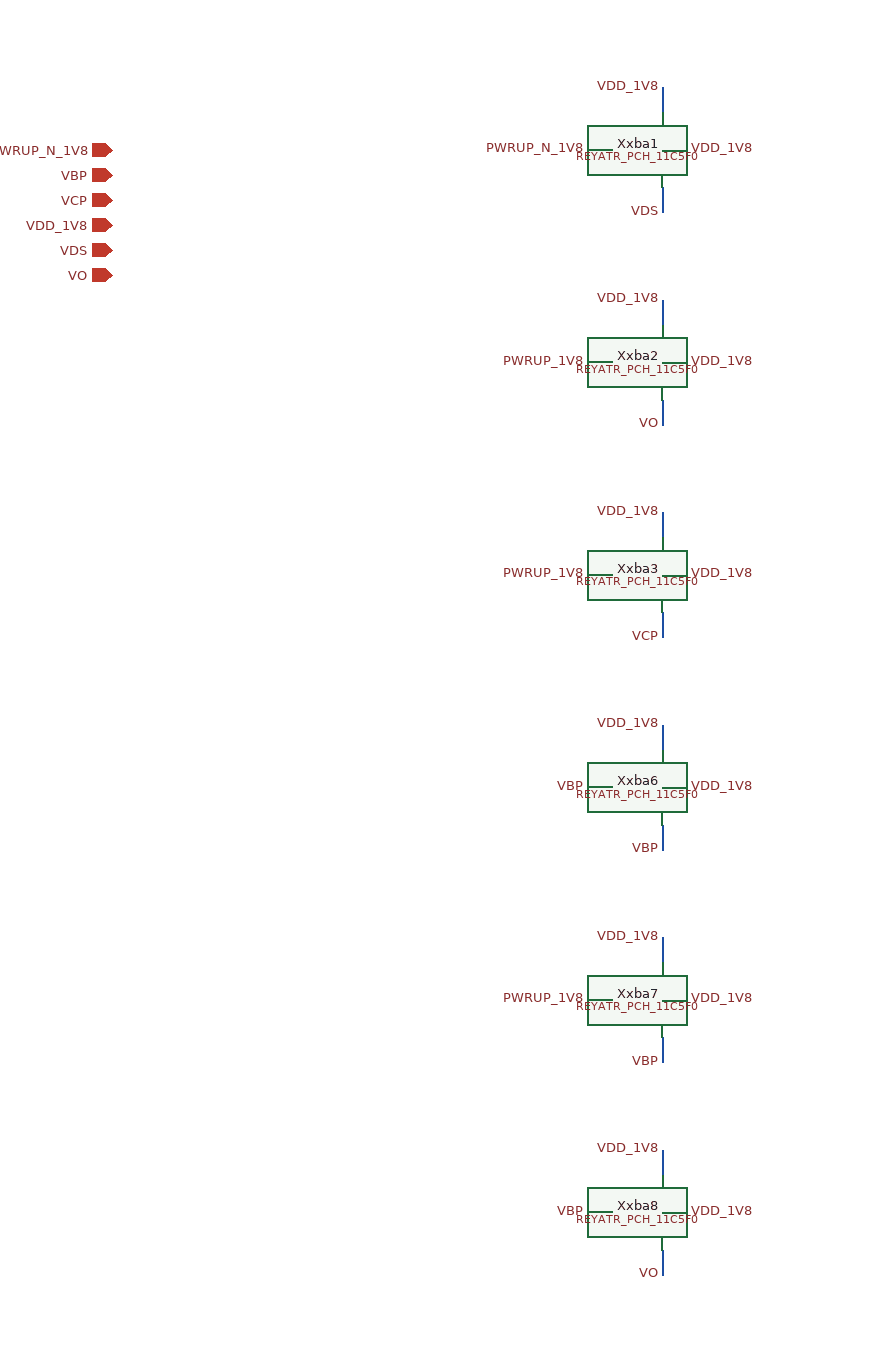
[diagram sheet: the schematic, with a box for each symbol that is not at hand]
v {xschem version=3.0.0 file_version=1.2 }
G {}
K {}
V {}
S {}
E {}
C {devices/iopin.sym} 0 0 0 0 {name=p0 lab=PWRUP_N_1V8}
C {devices/iopin.sym} 0 20 0 0 {name=p1 lab=VBP}
C {devices/iopin.sym} 0 40 0 0 {name=p2 lab=VCP}
C {devices/iopin.sym} 0 60 0 0 {name=p3 lab=VDD_1V8}
C {devices/iopin.sym} 0 80 0 0 {name=p4 lab=VDS}
C {devices/iopin.sym} 0 100 0 0 {name=p5 lab=VO}
C {LELO_TEMP_SKY130A/REYATR_PCH_11C5F0.sym} 400 0 0 0 {name=Xxba1}
N 440.0 50.0 440.0 30.0 {lab=VDS}
C {devices/lab_pin.sym} 440.0 50.0 1 0 {name=l0 sig_type=std_logic lab=VDS }
N 380.0 0.0 400.0 0.0 {lab=PWRUP_N_1V8}
C {devices/lab_pin.sym} 380.0 0.0 0 0 {name=l1 sig_type=std_logic lab=PWRUP_N_1V8 }
N 440.0 -50.0 440.0 -30.0 {lab=VDD_1V8}
C {devices/lab_pin.sym} 440.0 -50.0 3 0 {name=l2 sig_type=std_logic lab=VDD_1V8 }
N 460.0 0.0 440.0 0.0 {lab=VDD_1V8}
C {devices/lab_pin.sym} 460.0 0.0 2 0 {name=l3 sig_type=std_logic lab=VDD_1V8 }
C {LELO_TEMP_SKY130A/REYATR_PCH_11C5F0.sym} 400 170.0 0 0 {name=Xxba2}
N 440.0 220.0 440.0 200.0 {lab=VO}
C {devices/lab_pin.sym} 440.0 220.0 1 0 {name=l4 sig_type=std_logic lab=VO }
N 380.0 170.0 400.0 170.0 {lab=PWRUP_1V8}
C {devices/lab_pin.sym} 380.0 170.0 0 0 {name=l5 sig_type=std_logic lab=PWRUP_1V8 }
N 440.0 120.0 440.0 140.0 {lab=VDD_1V8}
C {devices/lab_pin.sym} 440.0 120.0 3 0 {name=l6 sig_type=std_logic lab=VDD_1V8 }
N 460.0 170.0 440.0 170.0 {lab=VDD_1V8}
C {devices/lab_pin.sym} 460.0 170.0 2 0 {name=l7 sig_type=std_logic lab=VDD_1V8 }
C {LELO_TEMP_SKY130A/REYATR_PCH_11C5F0.sym} 400 340.0 0 0 {name=Xxba3}
N 440.0 390.0 440.0 370.0 {lab=VCP}
C {devices/lab_pin.sym} 440.0 390.0 1 0 {name=l8 sig_type=std_logic lab=VCP }
N 380.0 340.0 400.0 340.0 {lab=PWRUP_1V8}
C {devices/lab_pin.sym} 380.0 340.0 0 0 {name=l9 sig_type=std_logic lab=PWRUP_1V8 }
N 440.0 290.0 440.0 310.0 {lab=VDD_1V8}
C {devices/lab_pin.sym} 440.0 290.0 3 0 {name=l10 sig_type=std_logic lab=VDD_1V8 }
N 460.0 340.0 440.0 340.0 {lab=VDD_1V8}
C {devices/lab_pin.sym} 460.0 340.0 2 0 {name=l11 sig_type=std_logic lab=VDD_1V8 }
C {LELO_TEMP_SKY130A/REYATR_PCH_11C5F0.sym} 400 510.0 0 0 {name=Xxba6}
N 440.0 560.0 440.0 540.0 {lab=VBP}
C {devices/lab_pin.sym} 440.0 560.0 1 0 {name=l12 sig_type=std_logic lab=VBP }
N 380.0 510.0 400.0 510.0 {lab=VBP}
C {devices/lab_pin.sym} 380.0 510.0 0 0 {name=l13 sig_type=std_logic lab=VBP }
N 440.0 460.0 440.0 480.0 {lab=VDD_1V8}
C {devices/lab_pin.sym} 440.0 460.0 3 0 {name=l14 sig_type=std_logic lab=VDD_1V8 }
N 460.0 510.0 440.0 510.0 {lab=VDD_1V8}
C {devices/lab_pin.sym} 460.0 510.0 2 0 {name=l15 sig_type=std_logic lab=VDD_1V8 }
C {LELO_TEMP_SKY130A/REYATR_PCH_11C5F0.sym} 400 680.0 0 0 {name=Xxba7}
N 440.0 730.0 440.0 710.0 {lab=VBP}
C {devices/lab_pin.sym} 440.0 730.0 1 0 {name=l16 sig_type=std_logic lab=VBP }
N 380.0 680.0 400.0 680.0 {lab=PWRUP_1V8}
C {devices/lab_pin.sym} 380.0 680.0 0 0 {name=l17 sig_type=std_logic lab=PWRUP_1V8 }
N 440.0 630.0 440.0 650.0 {lab=VDD_1V8}
C {devices/lab_pin.sym} 440.0 630.0 3 0 {name=l18 sig_type=std_logic lab=VDD_1V8 }
N 460.0 680.0 440.0 680.0 {lab=VDD_1V8}
C {devices/lab_pin.sym} 460.0 680.0 2 0 {name=l19 sig_type=std_logic lab=VDD_1V8 }
C {LELO_TEMP_SKY130A/REYATR_PCH_11C5F0.sym} 400 850.0 0 0 {name=Xxba8}
N 440.0 900.0 440.0 880.0 {lab=VO}
C {devices/lab_pin.sym} 440.0 900.0 1 0 {name=l20 sig_type=std_logic lab=VO }
N 380.0 850.0 400.0 850.0 {lab=VBP}
C {devices/lab_pin.sym} 380.0 850.0 0 0 {name=l21 sig_type=std_logic lab=VBP }
N 440.0 800.0 440.0 820.0 {lab=VDD_1V8}
C {devices/lab_pin.sym} 440.0 800.0 3 0 {name=l22 sig_type=std_logic lab=VDD_1V8 }
N 460.0 850.0 440.0 850.0 {lab=VDD_1V8}
C {devices/lab_pin.sym} 460.0 850.0 2 0 {name=l23 sig_type=std_logic lab=VDD_1V8 }
